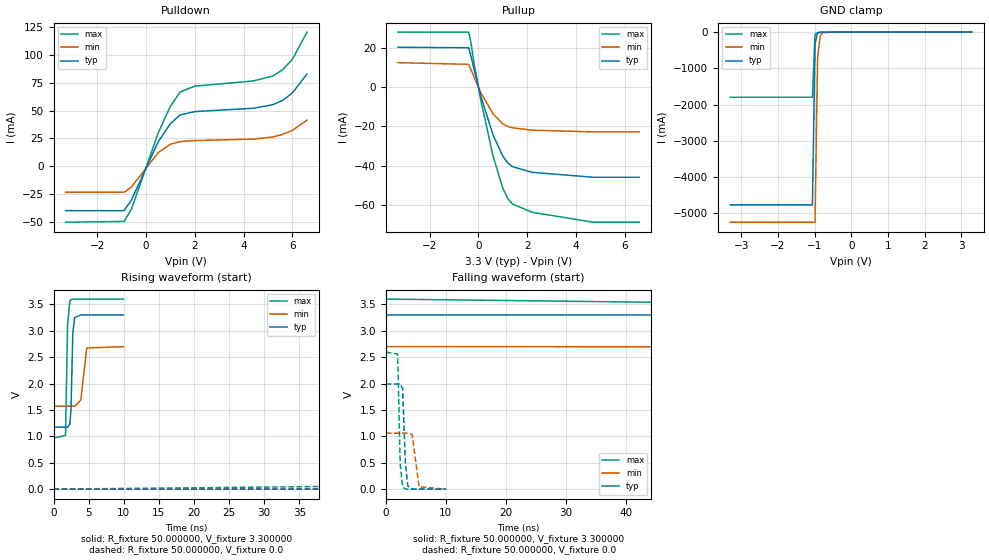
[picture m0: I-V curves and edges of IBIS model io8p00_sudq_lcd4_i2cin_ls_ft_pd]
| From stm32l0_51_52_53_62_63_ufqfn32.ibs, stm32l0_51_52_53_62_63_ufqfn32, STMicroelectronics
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|   Model io8p00_sudq_lcd4_i2cin_ls_ft_pd
[Model]  io8p00_sudq_lcd4_i2cin_ls_ft_pd
Model_type I/O
Polarity   Non-Inverting
Enable   Active-Low
Vinl =   0.990000V
Vinh =   2.310000V
Vmeas =  1.650000V
Cref =   50.000000pF
Rref =   100.000000M
Vref =   0.0V
C_comp   2.499500pF   2.460800pF   2.557800pF
[Temperature Range]   25.000000   0.125000k   -40.000000
[Pullup Reference]   3.300000V   2.700000V   3.600000V
[Pulldown Reference]   0.0V   0.0V   0.0V
[POWER Clamp Reference]   3.300000V   2.700000V   3.600000V
[GND Clamp Reference]   0.0V   0.0V   0.0V
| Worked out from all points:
|   slope of the pulldown table from 0 to 0.495 V, typ, clamps not added: 22.6 ohm
|   slope of the pullup table from 0 to 0.495 V, typ, clamps not added: 23.9 ohm
|   GND clamp passes 1 mA (typ) near -0.64 V on its own axis
|   rising waveform, R_fixture 50.000000, V_fixture 3.300000: 20-80 % time 216ps typ, 364ps min, 175ps max; typ from 1.18 V to 3.3 V
|   rising waveform, R_fixture 50.000000, V_fixture 0.0: 20-80 % time 203ns typ, 423ns min, 99.2ns max; typ from 0 V to 1.99 V
|   falling waveform, R_fixture 50.000000, V_fixture 3.300000: 20-80 % time 192ns typ, 382ns min, 105ns max; typ from 3.3 V to 1.18 V
|   falling waveform, R_fixture 50.000000, V_fixture 0.0: 20-80 % time 382ps typ, 549ps min, 305ps max; typ from 1.99 V to 0 V
[Pulldown]
|Voltage   I(typ)   I(min)   I(max)
-3.3V     -39.83mA   -23.36mA   -50.2mA
-900mV    -39.83mA   -23.36mA   -49.53mA
-600mV    -30.28mA   -18.59mA   -38.45mA
500mV     22.11mA    12.28mA    30.1mA
1V        38.33mA    19.81mA    53.88mA
1.4V      46.1mA     22.18mA    66.72mA
2V        49.07mA    23.02mA    71.93mA
4.4V      52.05mA    24.38mA    76.53mA
5.2V      55.25mA    26.3mA     81.02mA
5.6V      59.18mA    28.57mA    86.57mA
6V        65.78mA    32.24mA    95.96mA
6.6V      82.83mA    41.41mA    120.4mA
[Pullup]
|Voltage   I(typ)   I(min)   I(max)
-3.3V     20.5mA     12.63mA    28.27mA
-400mV    20.25mA    11.77mA    28.27mA
-300mV    15.65mA    8.931mA    22.44mA
-200mV    10.4mA     5.946mA    13.84mA
100mV     -4.685mA   -2.744mA   -6.647mA
600mV     -24.29mA   -13.56mA   -35.12mA
1V        -35.2mA    -18.69mA   -51.62mA
1.2V      -38.62mA   -19.99mA   -56.79mA
1.4V      -40.6mA    -20.72mA   -59.71mA
2.2V      -43.48mA   -21.92mA   -63.91mA
4.7V      -46mA      -22.8mA    -69mA
6.6V      -46mA      -22.8mA    -69mA
[GND_clamp]
|Voltage   I(typ)   I(min)   I(max)
-3.3V     -4.766A    -5.244A    -1.797A
-1.06V    -4.766A    -5.244A    -1.797A
-990mV    -326.4mA   -5.244A    -67.86mA
-920mV    -28.84mA   -721.7mA   -11.09mA
-850mV    -6.698mA   -104.1mA   -6.716mA
-780mV    -3.564mA   -17.3mA    -4.334mA
-500mV    -70.03uA   -187.2uA   -42.37uA
3.28V     73.94uA    88.61uA    51.47uA
[POWER_clamp]
|Voltage   I(typ)   I(min)   I(max)
-3.28V    0A         0A         0A
0V        0A         0A         0A
[Ramp]
| variable   typ   min   max
dV/dt_r  1.19406/0.20328u   0.61188/0.42519u   1.55520/99.09033n
dV/dt_f  1.27272/0.19144u   0.63720/0.38186u   1.57835/0.10505u
R_load = 50.000000
[Rising Waveform]
R_fixture= 50.000000
V_fixture= 3.300000
V_fixture_min= 2.700000
V_fixture_max= 3.600000
|time   V(typ)   V(min)   V(max)
0s        1.176V     1.571V     968.8mV
1.702ns   1.175V     1.571V     1.017V
2.002ns   1.172V     1.571V     3.12V
2.322ns   1.233V     1.571V     3.563V
2.482ns   1.502V     1.571V     3.587V
2.743ns   2.945V     1.57V      3.596V
3.003ns   3.251V     1.567V     3.598V
3.884ns   3.298V     1.687V     3.599V
4.725ns   3.298V     2.673V     3.599V
9.97ns    3.299V     2.698V     3.599V
[Rising Waveform]
R_fixture= 50.000000
V_fixture= 0.0
V_fixture_min= 0.0
V_fixture_max= 0.0
|time   V(typ)   V(min)   V(max)
0s        1.995nV    14.02nV    4.359nV
47.55ns   328.2uV    -21.62uV   62.37mV
100.1ns   75.34mV    5.97uV     913.5mV
165.2ns   455.1mV    5.32mV     1.937V
205.2ns   747.7mV    15.67mV    2.294V
252.8ns   1.074V     52.02mV    2.48V
387.9ns   1.677V     238.8mV    2.58V
538ns     1.909V     503.7mV    2.591V
883.4ns   1.986V     920.9mV    2.592V
1.246us   1.99V      1.06V      2.592V
[Falling Waveform]
R_fixture= 50.000000
V_fixture= 3.300000
V_fixture_min= 2.700000
V_fixture_max= 3.600000
|time   V(typ)   V(min)   V(max)
0s        3.299V     2.698V     3.599V
82.58ns   3.296V     2.695V     3.487V
150.2ns   3.187V     2.695V     2.485V
212.7ns   2.834V     2.692V     1.575V
247.7ns   2.592V     2.682V     1.235V
285.3ns   2.323V     2.66V      1.082V
385.4ns   1.663V     2.554V     998.9mV
485.5ns   1.348V     2.392V     979.5mV
815.8ns   1.196V     1.801V     969.4mV
1.246us   1.176V     1.571V     968.8mV
[Falling Waveform]
R_fixture= 50.000000
V_fixture= 0.0
V_fixture_min= 0.0
V_fixture_max= 0.0
|time   V(typ)   V(min)   V(max)
0s        1.99V      1.06V      2.592V
1.922ns   1.99V      1.06V      2.562V
2.022ns   1.99V      1.06V      2.306V
2.382ns   1.995V     1.06V      489.6mV
2.783ns   1.912V     1.06V      43.02mV
3.243ns   505.2mV    1.06V      3.568mV
3.664ns   57.91mV    1.061V     831.4uV
4.384ns   1.825mV    1.032V     335.7uV
5.526ns   254.9uV    44.77mV    139.4uV
9.97ns    1.995nV    14.02nV    4.359nV
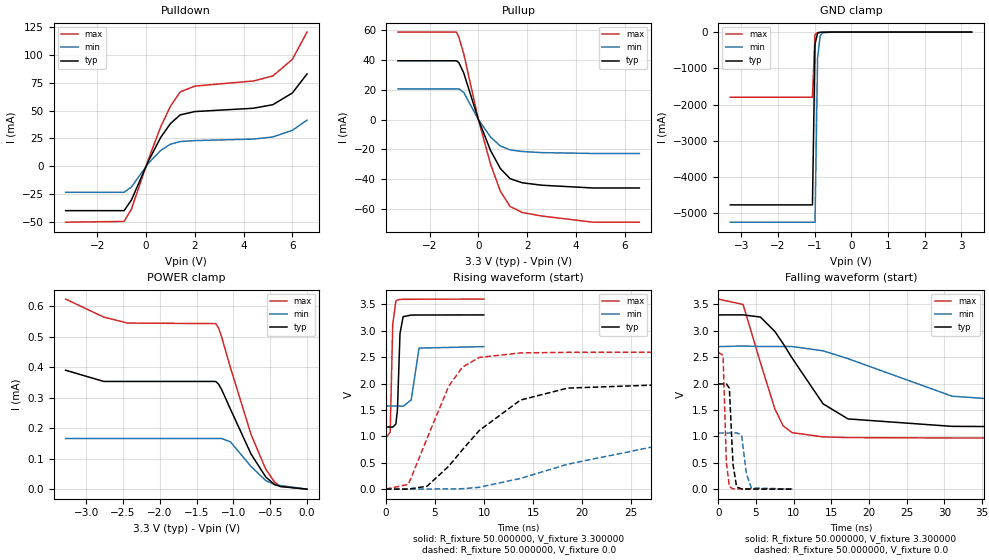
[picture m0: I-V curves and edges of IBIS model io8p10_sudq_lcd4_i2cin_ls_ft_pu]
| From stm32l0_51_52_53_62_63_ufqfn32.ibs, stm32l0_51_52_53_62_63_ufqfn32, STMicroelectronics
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|   Model io8p10_sudq_lcd4_i2cin_ls_ft_pu
[Model]  io8p10_sudq_lcd4_i2cin_ls_ft_pu
Model_type I/O
Polarity   Non-Inverting
Enable   Active-Low
Vinl =   0.990000V
Vinh =   2.310000V
Vmeas =  1.650000V
Cref =   50.000000pF
Rref =   100.000000M
Vref =   0.0V
C_comp   2.499500pF   2.460800pF   2.557800pF
[Temperature Range]   25.000000   0.125000k   -40.000000
[Pullup Reference]   3.300000V   2.700000V   3.600000V
[Pulldown Reference]   0.0V   0.0V   0.0V
[POWER Clamp Reference]   3.300000V   2.700000V   3.600000V
[GND Clamp Reference]   0.0V   0.0V   0.0V
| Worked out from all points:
|   slope of the pulldown table from 0 to 0.495 V, typ, clamps not added: 22.6 ohm
|   slope of the pullup table from 0 to 0.495 V, typ, clamps not added: 23.9 ohm
|   GND clamp passes 1 mA (typ) near -0.64 V on its own axis
|   rising waveform, R_fixture 50.000000, V_fixture 3.300000: 20-80 % time 215ps typ, 363ps min, 175ps max; typ from 1.18 V to 3.3 V
|   rising waveform, R_fixture 50.000000, V_fixture 0.0: 20-80 % time 6.52ns typ, 13.6ns min, 3.47ns max; typ from 0.001 V to 1.99 V
|   falling waveform, R_fixture 50.000000, V_fixture 3.300000: 20-80 % time 5.95ns typ, 12.6ns min, 3.26ns max; typ from 3.3 V to 1.18 V
|   falling waveform, R_fixture 50.000000, V_fixture 0.0: 20-80 % time 389ps typ, 558ps min, 312ps max; typ from 1.99 V to 0.001 V
[Pulldown]
|Voltage   I(typ)   I(min)   I(max)
-3.3V     -39.83mA   -23.36mA   -50.2mA
-900mV    -39.83mA   -23.36mA   -49.52mA
-600mV    -30.28mA   -18.59mA   -38.45mA
100mV     4.867mA    2.821mA    6.48mA
600mV     25.85mA    14.17mA    35.39mA
1V        38.33mA    19.81mA    53.88mA
1.4V      46.1mA     22.18mA    66.72mA
2V        49.07mA    23.02mA    71.93mA
4.4V      52.05mA    24.38mA    76.53mA
5.2V      55.25mA    26.31mA    81.02mA
6V        65.79mA    32.24mA    95.96mA
6.6V      82.83mA    41.41mA    120.4mA
[Pullup]
|Voltage   I(typ)   I(min)   I(max)
-3.3V     39.53mA    20.64mA    58.82mA
-900mV    39.53mA    20.64mA    58.82mA
-800mV    38.25mA    20.64mA    55.32mA
-600mV    31.26mA    18.2mA     44.19mA
0V        90fA       25.2pA     0A
500mV     -20.88mA   -11.78mA   -30.07mA
900mV     -32.92mA   -17.72mA   -48.14mA
1.3V      -39.75mA   -20.41mA   -58.47mA
1.8V      -42.5mA    -21.48mA   -62.49mA
2.6V      -44.14mA   -22.23mA   -64.85mA
4.7V      -46mA      -22.8mA    -69mA
6.6V      -46mA      -22.8mA    -69mA
[GND_clamp]
|Voltage   I(typ)   I(min)   I(max)
-3.3V     -4.766A    -5.244A    -1.797A
-1.06V    -4.766A    -5.244A    -1.797A
-990mV    -326.4mA   -5.244A    -67.85mA
-920mV    -28.83mA   -721.7mA   -11.08mA
-850mV    -6.686mA   -104.1mA   -6.707mA
-780mV    -3.552mA   -17.28mA   -4.326mA
-500mV    -59.41uA   -172uA     -34.91uA
3.28V     0A         0A         0A
[POWER_clamp]
|Voltage   I(typ)   I(min)   I(max)
-3.28V    390.5uA    166.4uA    624.1uA
-2.76V    353.6uA    166.4uA    564.7uA
-2.44V    353.6uA    166.4uA    545.3uA
-1.24V    353.6uA    166.4uA    543.5uA
-1.2V     344.2uA    166.4uA    528.2uA
-1.16V    327.1uA    166.4uA    499.5uA
-1.04V    262.6uA    155.2uA    398.8uA
-760mV    115.1uA    74.4uA     179.3uA
-560mV    39.87uA    27.94uA    65.07uA
-440mV    15uA       15.53uA    23.15uA
-360mV    8.745uA    12.05uA    9.091uA
0V        0A         0A         0A
[Ramp]
| variable   typ   min   max
dV/dt_r  1.19498/6.50137n   0.62975/13.58003n   1.55547/3.46138n
dV/dt_f  1.27308/5.94095n   0.65250/12.48638n   1.57816/3.25789n
R_load = 50.000000
[Rising Waveform]
R_fixture= 50.000000
V_fixture= 3.300000
V_fixture_min= 2.700000
V_fixture_max= 3.600000
|time   V(typ)   V(min)   V(max)
0s        1.178V     1.575V     969.7mV
440.4ps   1.177V     1.575V     1.08V
700.7ps   1.174V     1.575V     3.123V
1.021ns   1.233V     1.575V     3.56V
1.181ns   1.503V     1.575V     3.584V
1.441ns   2.949V     1.574V     3.593V
1.762ns   3.267V     1.57V      3.595V
2.583ns   3.297V     1.69V      3.595V
3.383ns   3.298V     2.671V     3.597V
9.97ns    3.3V       2.7V       3.6V
[Rising Waveform]
R_fixture= 50.000000
V_fixture= 0.0
V_fixture_min= 0.0
V_fixture_max= 0.0
|time   V(typ)   V(min)   V(max)
0s        1.061mV    1.811mV    1.02mV
2.302ns   1.606mV    157.9uV    92.02mV
4.204ns   56.24mV    3.616mV    963.8mV
6.406ns   433.8mV    3.878mV    1.95V
7.808ns   748.3mV    8.531mV    2.311V
9.51ns    1.109V     36mV       2.494V
13.71ns   1.687V     203mV      2.58V
18.52ns   1.914V     472.6mV    2.591V
30.23ns   1.99V      915.4mV    2.593V
49.85ns   1.993V     1.064V     2.593V
[Falling Waveform]
R_fixture= 50.000000
V_fixture= 3.300000
V_fixture_min= 2.700000
V_fixture_max= 3.600000
|time   V(typ)   V(min)   V(max)
0s        3.3V       2.7V       3.6V
3.303ns   3.301V     2.711V     3.497V
5.606ns   3.259V     2.702V     2.396V
7.508ns   2.988V     2.702V     1.525V
8.609ns   2.757V     2.701V     1.201V
9.81ns    2.483V     2.701V     1.071V
13.91ns   1.617V     2.62V      990.7mV
17.22ns   1.331V     2.472V     977.6mV
31.03ns   1.19V      1.761V     969.9mV
49.85ns   1.178V     1.575V     969.7mV
[Falling Waveform]
R_fixture= 50.000000
V_fixture= 0.0
V_fixture_min= 0.0
V_fixture_max= 0.0
|time   V(typ)   V(min)   V(max)
0s        1.993V     1.064V     2.593V
640.6ps   1.993V     1.064V     2.536V
1.081ns   1.997V     1.064V     512.6mV
1.481ns   1.912V     1.064V     49.83mV
1.962ns   472.6mV    1.064V     8.037mV
2.442ns   44.92mV    1.068V     5.601mV
3.103ns   5.611mV    1.023V     5.385mV
3.744ns   4.245mV    291mV      5.567mV
4.404ns   4.133mV    23.48mV    3.612mV
9.97ns    1.061mV    1.811mV    1.02mV
